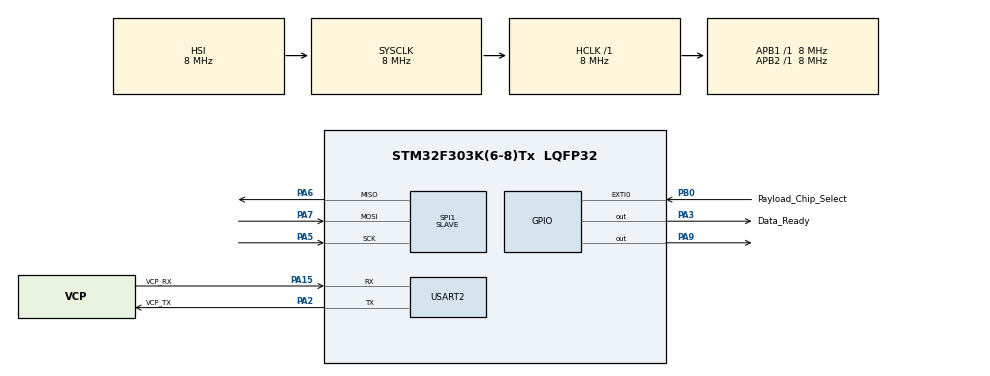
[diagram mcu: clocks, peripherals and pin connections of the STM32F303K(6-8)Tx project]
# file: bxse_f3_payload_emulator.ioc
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Mcu.Family=STM32F3
Mcu.Name=STM32F303K(6-8)Tx
Mcu.Package=LQFP32
NVIC.EXTI0_IRQn=true\:6\:0\:true\:false\:true\:true\:true\:true
NVIC.PriorityGroup=NVIC_PRIORITYGROUP_4
NVIC.SPI1_IRQn=true\:5\:0\:true\:false\:true\:true\:true\:true
PA13.GPIO_Label=SWDIO
PA13.Mode=Serial_Wire
PA13.Signal=SYS_JTMS-SWDIO
PA14.GPIO_Label=SWCLK
PA14.Mode=Serial_Wire
PA14.Signal=SYS_JTCK-SWCLK
PA15.GPIO_Label=VCP_RX
PA15.Mode=Asynchronous
PA15.Signal=USART2_RX
PA2.GPIO_Label=VCP_TX
PA2.Mode=Asynchronous
PA2.Signal=USART2_TX
PA3.GPIO_Label=Data_Ready
PA3.GPIO_PuPd=GPIO_PULLDOWN
PA3.Signal=GPIO_Output
PA5.Mode=Full_Duplex_Slave
PA5.Signal=SPI1_SCK
PA6.Mode=Full_Duplex_Slave
PA6.Signal=SPI1_MISO
PA7.Mode=Full_Duplex_Slave
PA7.Signal=SPI1_MOSI
PA9.Signal=GPIO_Output
PB0.GPIO_Label=Payload_Chip_Select
PB0.GPIO_PuPd=GPIO_PULLDOWN
PB0.Signal=GPXTI0
PF0\ /\ OSC_IN.GPIO_Label=MCO
PF0\ /\ OSC_IN.Mode=HSE-External-Clock-Source
PF0\ /\ OSC_IN.Signal=RCC_OSC_IN
ProjectManager.HeapSize=0x200
ProjectManager.StackSize=0x400
ProjectManager.TargetToolchain=STM32CubeIDE
RCC.AHBFreq_Value=8000000
RCC.APB1Freq_Value=8000000
RCC.APB2Freq_Value=8000000
RCC.CortexFreq_Value=8000000
RCC.HSE_VALUE=8000000
RCC.HSI_VALUE=8000000
RCC.SYSCLKFreq_VALUE=8000000
SPI1.DataSize=SPI_DATASIZE_8BIT
SPI1.Direction=SPI_DIRECTION_2LINES
SPI1.Mode=SPI_MODE_SLAVE
SPI1.VirtualType=VM_SLAVE
USART2.VirtualMode-Asynchronous=VM_ASYNC
board=NUCLEO-F303K8

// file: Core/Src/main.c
/* USER CODE BEGIN Header */
/**
 ******************************************************************************
 * @file           : main.c
 * @brief          : Main program body
 ******************************************************************************
 * @attention
 *
 * Copyright (c) 2023 STMicroelectronics.
 * All rights reserved.
 *
 * This software is licensed under terms that can be found in the LICENSE file
 * in the root directory of this software component.
 * If no LICENSE file comes with this software, it is provided AS-IS.
 *
 ******************************************************************************
 */
/* USER CODE END Header */
#include "main.h"

SPI_HandleTypeDef hspi1;

UART_HandleTypeDef huart2;

/* USER CODE BEGIN PV */
// Data size as defined by emulator largest packet size
#define kDataSize 200
// Create a buffer where you will store the data
uint8_t buffer[kDataSize];

/* USER CODE END PV */

void SystemClock_Config(void);
static void MX_GPIO_Init(void);
static void MX_USART2_UART_Init(void);
static void MX_SPI1_Init(void);

int main(void) {

  /* MCU Configuration--------------------------------------------------------*/

  /* Reset of all peripherals, Initializes the Flash interface and the Systick.
   */
  HAL_Init();

  /* Configure the system clock */
  SystemClock_Config();

  /* Initialize all configured peripherals */
  MX_GPIO_Init();
  MX_USART2_UART_Init();
  MX_SPI1_Init();
  /* USER CODE BEGIN 2 */

  // This is random data to send
  uint8_t random_msg[] = "This is the random payload data \n";

  // We need to copy the data into the buffer we created
  for (uint16_t i = 0; i < sizeof(random_msg); i++) {
    buffer[i] = random_msg[i];
  }

  /* USER CODE END 2 */

  /* Infinite loop */
  /* USER CODE BEGIN WHILE */
  while (1) {
	  // Make sure the GPIO is set to low
	  HAL_GPIO_WritePin(PL_GPIO_Port, PL_Pin, GPIO_PIN_RESET);

    // Wait for the Emulator to be ready.
    if (HAL_GPIO_ReadPin(PL_Wait_GPIO_Port, PL_Wait_Pin) == GPIO_PIN_SET) {

    	// To transmit the data we need to call this function
    	HAL_StatusTypeDef status = HAL_SPI_Transmit_IT(&hspi1, buffer, kDataSize);
    	// then we can toggle the GPIO to let the emulator know we are ready to transmit
    	HAL_GPIO_WritePin(PL_GPIO_Port, PL_Pin,GPIO_PIN_SET);
    	HAL_Delay(10);
    }

    /* USER CODE END WHILE */

  }
}

void SystemClock_Config(void) {
  RCC_OscInitTypeDef RCC_OscInitStruct = {0};
  RCC_ClkInitTypeDef RCC_ClkInitStruct = {0};

  /** Initializes the RCC Oscillators according to the specified parameters
   * in the RCC_OscInitTypeDef structure.
   */
  RCC_OscInitStruct.OscillatorType = RCC_OSCILLATORTYPE_HSI;
  RCC_OscInitStruct.HSIState = RCC_HSI_ON;
  RCC_OscInitStruct.HSICalibrationValue = RCC_HSICALIBRATION_DEFAULT;
  RCC_OscInitStruct.PLL.PLLState = RCC_PLL_NONE;
  if (HAL_RCC_OscConfig(&RCC_OscInitStruct) != HAL_OK) {
    Error_Handler();
  }

  /** Initializes the CPU, AHB and APB buses clocks
   */
  RCC_ClkInitStruct.ClockType = RCC_CLOCKTYPE_HCLK | RCC_CLOCKTYPE_SYSCLK |
                                RCC_CLOCKTYPE_PCLK1 | RCC_CLOCKTYPE_PCLK2;
  RCC_ClkInitStruct.SYSCLKSource = RCC_SYSCLKSOURCE_HSI;
  RCC_ClkInitStruct.AHBCLKDivider = RCC_SYSCLK_DIV1;
  RCC_ClkInitStruct.APB1CLKDivider = RCC_HCLK_DIV1;
  RCC_ClkInitStruct.APB2CLKDivider = RCC_HCLK_DIV1;

  if (HAL_RCC_ClockConfig(&RCC_ClkInitStruct, FLASH_LATENCY_0) != HAL_OK) {
    Error_Handler();
  }
}

static void MX_SPI1_Init(void) {

  /* SPI1 parameter configuration*/
  hspi1.Instance = SPI1;
  hspi1.Init.Mode = SPI_MODE_SLAVE;
  hspi1.Init.Direction = SPI_DIRECTION_2LINES;
  hspi1.Init.DataSize = SPI_DATASIZE_8BIT;
  hspi1.Init.CLKPolarity = SPI_POLARITY_LOW;
  hspi1.Init.CLKPhase = SPI_PHASE_1EDGE;
  hspi1.Init.NSS = SPI_NSS_SOFT;
  hspi1.Init.FirstBit = SPI_FIRSTBIT_MSB;
  hspi1.Init.TIMode = SPI_TIMODE_DISABLE;
  hspi1.Init.CRCCalculation = SPI_CRCCALCULATION_DISABLE;
  hspi1.Init.CRCPolynomial = 7;
  hspi1.Init.CRCLength = SPI_CRC_LENGTH_DATASIZE;
  hspi1.Init.NSSPMode = SPI_NSS_PULSE_DISABLE;
  if (HAL_SPI_Init(&hspi1) != HAL_OK) {
    Error_Handler();
  }
}

static void MX_USART2_UART_Init(void) {

  huart2.Instance = USART2;
  huart2.Init.BaudRate = 38400;
  huart2.Init.WordLength = UART_WORDLENGTH_8B;
  huart2.Init.StopBits = UART_STOPBITS_1;
  huart2.Init.Parity = UART_PARITY_NONE;
  huart2.Init.Mode = UART_MODE_TX_RX;
  huart2.Init.HwFlowCtl = UART_HWCONTROL_NONE;
  huart2.Init.OverSampling = UART_OVERSAMPLING_16;
  huart2.Init.OneBitSampling = UART_ONE_BIT_SAMPLE_DISABLE;
  huart2.AdvancedInit.AdvFeatureInit = UART_ADVFEATURE_NO_INIT;
  if (HAL_UART_Init(&huart2) != HAL_OK) {
    Error_Handler();
  }
}

static void MX_GPIO_Init(void) {
  GPIO_InitTypeDef GPIO_InitStruct = {0};

  /* GPIO Ports Clock Enable */
  __HAL_RCC_GPIOF_CLK_ENABLE();
  __HAL_RCC_GPIOA_CLK_ENABLE();
  __HAL_RCC_GPIOB_CLK_ENABLE();

  /*Configure GPIO pin Output Level */
  HAL_GPIO_WritePin(PL_GPIO_Port, PL_Pin, GPIO_PIN_RESET);

  /*Configure GPIO pin : PL_Pin */
  GPIO_InitStruct.Pin = PL_Pin;
  GPIO_InitStruct.Mode = GPIO_MODE_OUTPUT_PP;
  GPIO_InitStruct.Pull = GPIO_NOPULL;
  GPIO_InitStruct.Speed = GPIO_SPEED_FREQ_LOW;
  HAL_GPIO_Init(PL_GPIO_Port, &GPIO_InitStruct);

  /*Configure GPIO pin : PL_Wait_Pin */
  GPIO_InitStruct.Pin = PL_Wait_Pin;
  GPIO_InitStruct.Mode = GPIO_MODE_INPUT;
  GPIO_InitStruct.Pull = GPIO_NOPULL;
  HAL_GPIO_Init(PL_Wait_GPIO_Port, &GPIO_InitStruct);

}

void Error_Handler(void) {
  __disable_irq();
  while (1) {
  }
}

#ifdef USE_FULL_ASSERT
/**
 * @brief  Reports the name of the source file and the source line number
 *         where the assert_param error has occurred.
 * @param  file: pointer to the source file name
 * @param  line: assert_param error line source number
 * @retval None
 */
void assert_failed(uint8_t *file, uint32_t line) {
  /* USER CODE BEGIN 6 */
  /* User can add his own implementation to report the file name and line
     number, ex: printf("Wrong parameters value: file %s on line %d\r\n", file,
     line) */
  /* USER CODE END 6 */
}
#endif /* USE_FULL_ASSERT */
